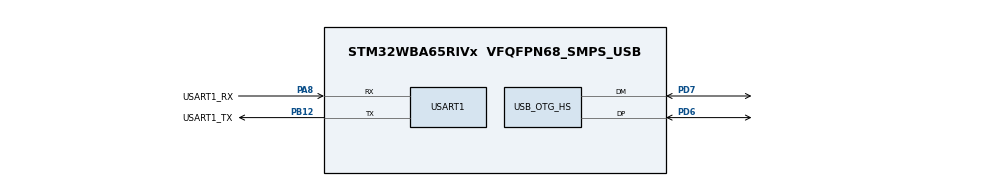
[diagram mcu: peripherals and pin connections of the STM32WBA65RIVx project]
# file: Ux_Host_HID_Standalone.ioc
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CORTEX_M33_NS.userName=CORTEX_M33
Mcu.Family=STM32WBA
Mcu.Name=STM32WBA65RIVx
Mcu.Package=VFQFPN68_SMPS_USB
NVIC.PriorityGroup=NVIC_PRIORITYGROUP_4
NVIC.USB_OTG_HS_IRQn=true\:7\:0\:true\:false\:true\:true\:true\:true
OSC_IN.Mode=HSE-External-Oscillator
OSC_IN.PinAttribute=CortexM33
OSC_IN.Signal=RCC_OSC_IN
OSC_OUT.Mode=HSE-External-Oscillator
OSC_OUT.PinAttribute=CortexM33
OSC_OUT.Signal=RCC_OSC_OUT
PA8.GPIO_Label=USART1_RX
PA8.GPIO_Speed=GPIO_SPEED_FREQ_HIGH
PA8.Mode=Asynchronous
PA8.PinAttribute=CortexM33
PA8.Signal=USART1_RX
PB12.GPIO_Label=USART1_TX
PB12.GPIO_Speed=GPIO_SPEED_FREQ_HIGH
PB12.Mode=Asynchronous
PB12.PinAttribute=CortexM33
PB12.Signal=USART1_TX
PD6.Mode=Internal_Phy_Host
PD6.PinAttribute=CortexM33
PD6.Signal=USB_OTG_HS_DP
PD7.Mode=Internal_Phy_Host
PD7.PinAttribute=CortexM33
PD7.Signal=USB_OTG_HS_DM
ProjectManager.HeapSize=0x200
ProjectManager.StackSize=0x400
ProjectManager.TargetToolchain=EWARM V9.60
RCC.ADCFreq_Value=100000000
RCC.AHB5CLKDivider=DIV4
RCC.AHBFreq_Value=100000000
RCC.APB1Freq_Value=100000000
RCC.APB1TimFreq_Value=100000000
RCC.APB2Freq_Value=100000000
RCC.APB2TimFreq_Value=100000000
RCC.CortexFreq_Value=12500000
RCC.HCLKFreq_Value=100000000
RCC.HSE_VALUE=32000000
RCC.HSI_VALUE=16000000
RCC.LSE_VALUE=32768
RCC.LSI1_VALUE=32000
RCC.LSI2_VALUE=32000
RCC.PLLFRACN=4096
RCC.PLLM=2
RCC.PLLN=12
RCC.PLLSourceVirtual=RCC_PLLSOURCE_HSE
RCC.SYSCLKFreq_VALUE=100000000
RCC.SYSCLKSourceVirtual=RCC_SYSCLKSOURCE_PLLCLK
RCC.VCOOutputFreq_Value=200000000
USART1.VirtualMode-Asynchronous=VM_ASYNC
USBX.BSP.number=1
USBX.Core_System=1
USBX.USBX_SYS_SIZE=1024 * 24
USBX.UX_ALIGN_MIN=UX_ALIGN_8
USBX.UX_APP_MEM_POOL_SIZE_STANDALONE=1024 * 24
USBX.UX_HOST_APP_MEM_POOL_SIZE=1024 * 28
USBX.UX_HOST_APP_MEM_POOL_SIZE_STANDALONE=1024 * 24 
USBX.UX_HOST_CLASS_HID_KEYBOARD_EVENTS_KEY_CHANGES_MODE=1
USBX.UX_HOST_CLASS_HID_KEYBOARD_EVENTS_KEY_CHANGES_MODE_REPORT_KEY_DOWN_ONLY=1
USBX.UX_HOST_CLASS_HID_KEYBOARD_EVENTS_KEY_CHANGES_MODE_REPORT_LOCK_KEYS=1
USBX.UX_HOST_CLASS_HID_KEYBOARD_EVENTS_KEY_CHANGES_MODE_REPORT_MODIFIER_KEYS=1
USBX.UX_HOST_enabled_HS=1
USBX.UX_Host_Controller=1
USBX.UX_Host_CoreStack=1
USBX.UX_Host_class_HID_Core=1
USBX.UX_Host_class_HID_Keyboard=1
USBX.UX_Host_class_HID_Mouse=1
USBX.UX_MAX_CLASS_DRIVER=3
USBX.UX_MAX_ED=80
USBX.UX_MAX_ISO_TD=1
USBX.UX_MAX_TD=128
USBX0.BSP.STBoard=false
USBX0.BSP.api=Unknown
USBX0.BSP.condition=SEMAOoUSBOoOTGOoHSOoHOSTOoFOROoUSBX
USBX0.BSP.instance=USB_OTG_HS
USBX0.BSP.ip=USB_OTG_HS
USBX0.BSP.mode=Host_Only
USBX0.BSP.name=USB_Host
USBX0.BSP.solution=USB_OTG_HS
USB_OTG_HS.RefClockSelection=SYSCFG_OTG_HS_PHY_CLK_SELECT_6
USB_OTG_HS.VirtualMode=Host_HS
USB_OTG_HS.use_external_vbus=DISABLE
VP_CORTEX_M33_NS_VS_Hclk.Mode=Hclk_Mode
VP_ICACHE_VS_ICACHE.Mode=DirectMappedCache
VP_PWR_VS_SECSignals.Mode=Security/Privilege
VP_USBX_Core_System.Mode=Core_System
VP_USBX_UX\ Host\ Controller_HS.Mode=UX_Host_Controller_HS
VP_USBX_UX\ Host\ CoreStack_HS.Mode=UX_Host_CoreStack_HS
VP_USBX_UX\ Host\ HID\ Core_HS.Mode=UX_Host_class_HID_Core_HS
VP_USBX_UX\ Host\ HID\ Keyboard_HS.Mode=UX_Host_class_HID_Keyboard_HS
VP_USBX_UX\ Host\ HID\ Mouse_HS.Mode=UX_Host_class_HID_Mouse_HS
board=custom

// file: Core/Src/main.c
/* USER CODE BEGIN Header */
/**
  ******************************************************************************
  * @file           : main.c
  * @brief          : Main program body
  ******************************************************************************
  * @attention
  *
  * Copyright (c) 2025 STMicroelectronics.
  * All rights reserved.
  *
  * This software is licensed under terms that can be found in the LICENSE file
  * in the root directory of this software component.
  * If no LICENSE file comes with this software, it is provided AS-IS.
  *
  ******************************************************************************
  */
/* USER CODE END Header */
#include "main.h"
#include "app_usbx.h"

/* USER CODE BEGIN Includes */
#if defined(__ICCARM__)
#include <LowLevelIOInterface.h>
#endif /* __ICCARM__ */
/* USER CODE END Includes */

UART_HandleTypeDef huart1;

HCD_HandleTypeDef hhcd_USB_OTG_HS;

void SystemClock_Config(void);
static void MX_GPIO_Init(void);
static void MX_ICACHE_Init(void);
static void MX_USART1_UART_Init(void);
/* USER CODE BEGIN PFP */
#if defined(__ICCARM__)
/* New definition from EWARM V9, compatible with EWARM8 */
int iar_fputc(int ch);
#define PUTCHAR_PROTOTYPE int iar_fputc(int ch)
#elif defined ( __CC_ARM ) || defined(__ARMCC_VERSION)
/* ARM Compiler 5/6*/
#define PUTCHAR_PROTOTYPE int fputc(int ch, FILE *f)
#elif defined(__GNUC__)
#define PUTCHAR_PROTOTYPE int __io_putchar(int ch)
#endif /* __ICCARM__ */
/* USER CODE END PFP */

int main(void)
{

  /* MCU Configuration--------------------------------------------------------*/

  /* Reset of all peripherals, Initializes the Flash interface and the Systick. */
  HAL_Init();

  /* Configure the system clock */
  SystemClock_Config();

  /* Initialize all configured peripherals */
  MX_GPIO_Init();
  MX_ICACHE_Init();
  MX_USART1_UART_Init();
  MX_USBX_Init();

  /* Infinite loop */
  while (1)
  {

    /* USER CODE BEGIN 3 */
    USBX_Host_Process(NULL);
  }
  /* USER CODE END 3 */
}

void SystemClock_Config(void)
{
  RCC_OscInitTypeDef RCC_OscInitStruct = {0};
  RCC_ClkInitTypeDef RCC_ClkInitStruct = {0};

  /** Supply configuration update enable
  */
  HAL_PWREx_ConfigSupply(PWR_LDO_SUPPLY);

  /** Configure the main internal regulator output voltage
  */
  if (HAL_PWREx_ControlVoltageScaling(PWR_REGULATOR_VOLTAGE_SCALE1) != HAL_OK)
  {
    Error_Handler();
  }

  /** Initializes the CPU, AHB and APB busses clocks
  */
  RCC_OscInitStruct.OscillatorType = RCC_OSCILLATORTYPE_HSE;
  RCC_OscInitStruct.HSEState = RCC_HSE_ON;
  RCC_OscInitStruct.HSEDiv = RCC_HSE_DIV1;
  RCC_OscInitStruct.PLL1.PLLState = RCC_PLL_ON;
  RCC_OscInitStruct.PLL1.PLLSource = RCC_PLLSOURCE_HSE;
  RCC_OscInitStruct.PLL1.PLLM = 2;
  RCC_OscInitStruct.PLL1.PLLN = 12;
  RCC_OscInitStruct.PLL1.PLLP = 2;
  RCC_OscInitStruct.PLL1.PLLQ = 2;
  RCC_OscInitStruct.PLL1.PLLR = 2;
  RCC_OscInitStruct.PLL1.PLLFractional = 4096;
  if (HAL_RCC_OscConfig(&RCC_OscInitStruct) != HAL_OK)
  {
    Error_Handler();
  }

  /** Initializes the CPU, AHB and APB busses clocks
  */
  RCC_ClkInitStruct.ClockType = RCC_CLOCKTYPE_HCLK|RCC_CLOCKTYPE_SYSCLK
                              |RCC_CLOCKTYPE_PCLK1|RCC_CLOCKTYPE_PCLK2
                              |RCC_CLOCKTYPE_PCLK7|RCC_CLOCKTYPE_HCLK5;
  RCC_ClkInitStruct.SYSCLKSource = RCC_SYSCLKSOURCE_PLLCLK;
  RCC_ClkInitStruct.AHBCLKDivider = RCC_SYSCLK_DIV1;
  RCC_ClkInitStruct.APB1CLKDivider = RCC_HCLK_DIV1;
  RCC_ClkInitStruct.APB2CLKDivider = RCC_HCLK_DIV1;
  RCC_ClkInitStruct.APB7CLKDivider = RCC_HCLK_DIV1;
  RCC_ClkInitStruct.AHB5_PLL1_CLKDivider = RCC_SYSCLK_PLL1_DIV4;
  RCC_ClkInitStruct.AHB5_HSEHSI_CLKDivider = RCC_SYSCLK_HSEHSI_DIV1;

  if (HAL_RCC_ClockConfig(&RCC_ClkInitStruct, FLASH_LATENCY_3) != HAL_OK)
  {
    Error_Handler();
  }
}

static void MX_ICACHE_Init(void)
{

  /** Enable instruction cache in 1-way (direct mapped cache)
  */
  if (HAL_ICACHE_ConfigAssociativityMode(ICACHE_1WAY) != HAL_OK)
  {
    Error_Handler();
  }
  if (HAL_ICACHE_Enable() != HAL_OK)
  {
    Error_Handler();
  }

}

static void MX_USART1_UART_Init(void)
{

  huart1.Instance = USART1;
  huart1.Init.BaudRate = 115200;
  huart1.Init.WordLength = UART_WORDLENGTH_8B;
  huart1.Init.StopBits = UART_STOPBITS_1;
  huart1.Init.Parity = UART_PARITY_NONE;
  huart1.Init.Mode = UART_MODE_TX_RX;
  huart1.Init.HwFlowCtl = UART_HWCONTROL_NONE;
  huart1.Init.OverSampling = UART_OVERSAMPLING_16;
  huart1.Init.OneBitSampling = UART_ONE_BIT_SAMPLE_DISABLE;
  huart1.Init.ClockPrescaler = UART_PRESCALER_DIV1;
  huart1.AdvancedInit.AdvFeatureInit = UART_ADVFEATURE_NO_INIT;
  if (HAL_UART_Init(&huart1) != HAL_OK)
  {
    Error_Handler();
  }
  if (HAL_UARTEx_SetTxFifoThreshold(&huart1, UART_TXFIFO_THRESHOLD_1_8) != HAL_OK)
  {
    Error_Handler();
  }
  if (HAL_UARTEx_SetRxFifoThreshold(&huart1, UART_RXFIFO_THRESHOLD_1_8) != HAL_OK)
  {
    Error_Handler();
  }
  if (HAL_UARTEx_DisableFifoMode(&huart1) != HAL_OK)
  {
    Error_Handler();
  }

}

void MX_USB_OTG_HS_HCD_Init(void)
{

  hhcd_USB_OTG_HS.Instance = USB_OTG_HS;
  hhcd_USB_OTG_HS.Init.Host_channels = 16;
  hhcd_USB_OTG_HS.Init.speed = HCD_SPEED_HIGH;
  hhcd_USB_OTG_HS.Init.dma_enable = DISABLE;
  hhcd_USB_OTG_HS.Init.phy_itface = USB_OTG_HS_EMBEDDED_PHY;
  hhcd_USB_OTG_HS.Init.Sof_enable = DISABLE;
  hhcd_USB_OTG_HS.Init.low_power_enable = DISABLE;
  hhcd_USB_OTG_HS.Init.use_external_vbus = DISABLE;
  if (HAL_HCD_Init(&hhcd_USB_OTG_HS) != HAL_OK)
  {
    Error_Handler();
  }

}

static void MX_GPIO_Init(void)
{

  /* GPIO Ports Clock Enable */
  __HAL_RCC_GPIOB_CLK_ENABLE();
  __HAL_RCC_GPIOA_CLK_ENABLE();
  __HAL_RCC_GPIOD_CLK_ENABLE();

}

/* USER CODE BEGIN 4 */

/**
  * @brief  Retargets the C library __write function to the IAR function iar_fputc.
  * @param  file: file descriptor.
  * @param  ptr: pointer to the buffer where the data is stored.
  * @param  len: length of the data to write in bytes.
  * @retval length of the written data in bytes.
  */
#if defined(__ICCARM__)
size_t __write(int file, unsigned char const *ptr, size_t len)
{
  size_t idx;
  unsigned char const *pdata = ptr;

  for (idx = 0; idx < len; idx++)
  {
    iar_fputc((int)*pdata);
    pdata++;
  }
  return len;
}
#endif /* __ICCARM__ */

/**
  * @brief  Retargets the C library printf function to the USART.
  * @param  None
  * @retval None
  */
PUTCHAR_PROTOTYPE
{
  /* Place your implementation of fputc here */
  /* e.g. write a character to the USART1 and Loop until the end of transmission */
  HAL_UART_Transmit(&huart1, (uint8_t *)&ch, 1, 0xFFFF);

  return ch;
}
/* USER CODE END 4 */

void Error_Handler(void)
{
  while (1)
  {
  }
}
